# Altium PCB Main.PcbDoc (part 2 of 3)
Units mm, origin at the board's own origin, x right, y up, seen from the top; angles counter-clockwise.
Board outline 160.02 x 109 mm, 4 copper layers (Top Layer, MidLayer1, MidLayer2, Bottom Layer), stack 1.588 mm thick; 313 components, 266 nets, 1154 pads, 499 vias.

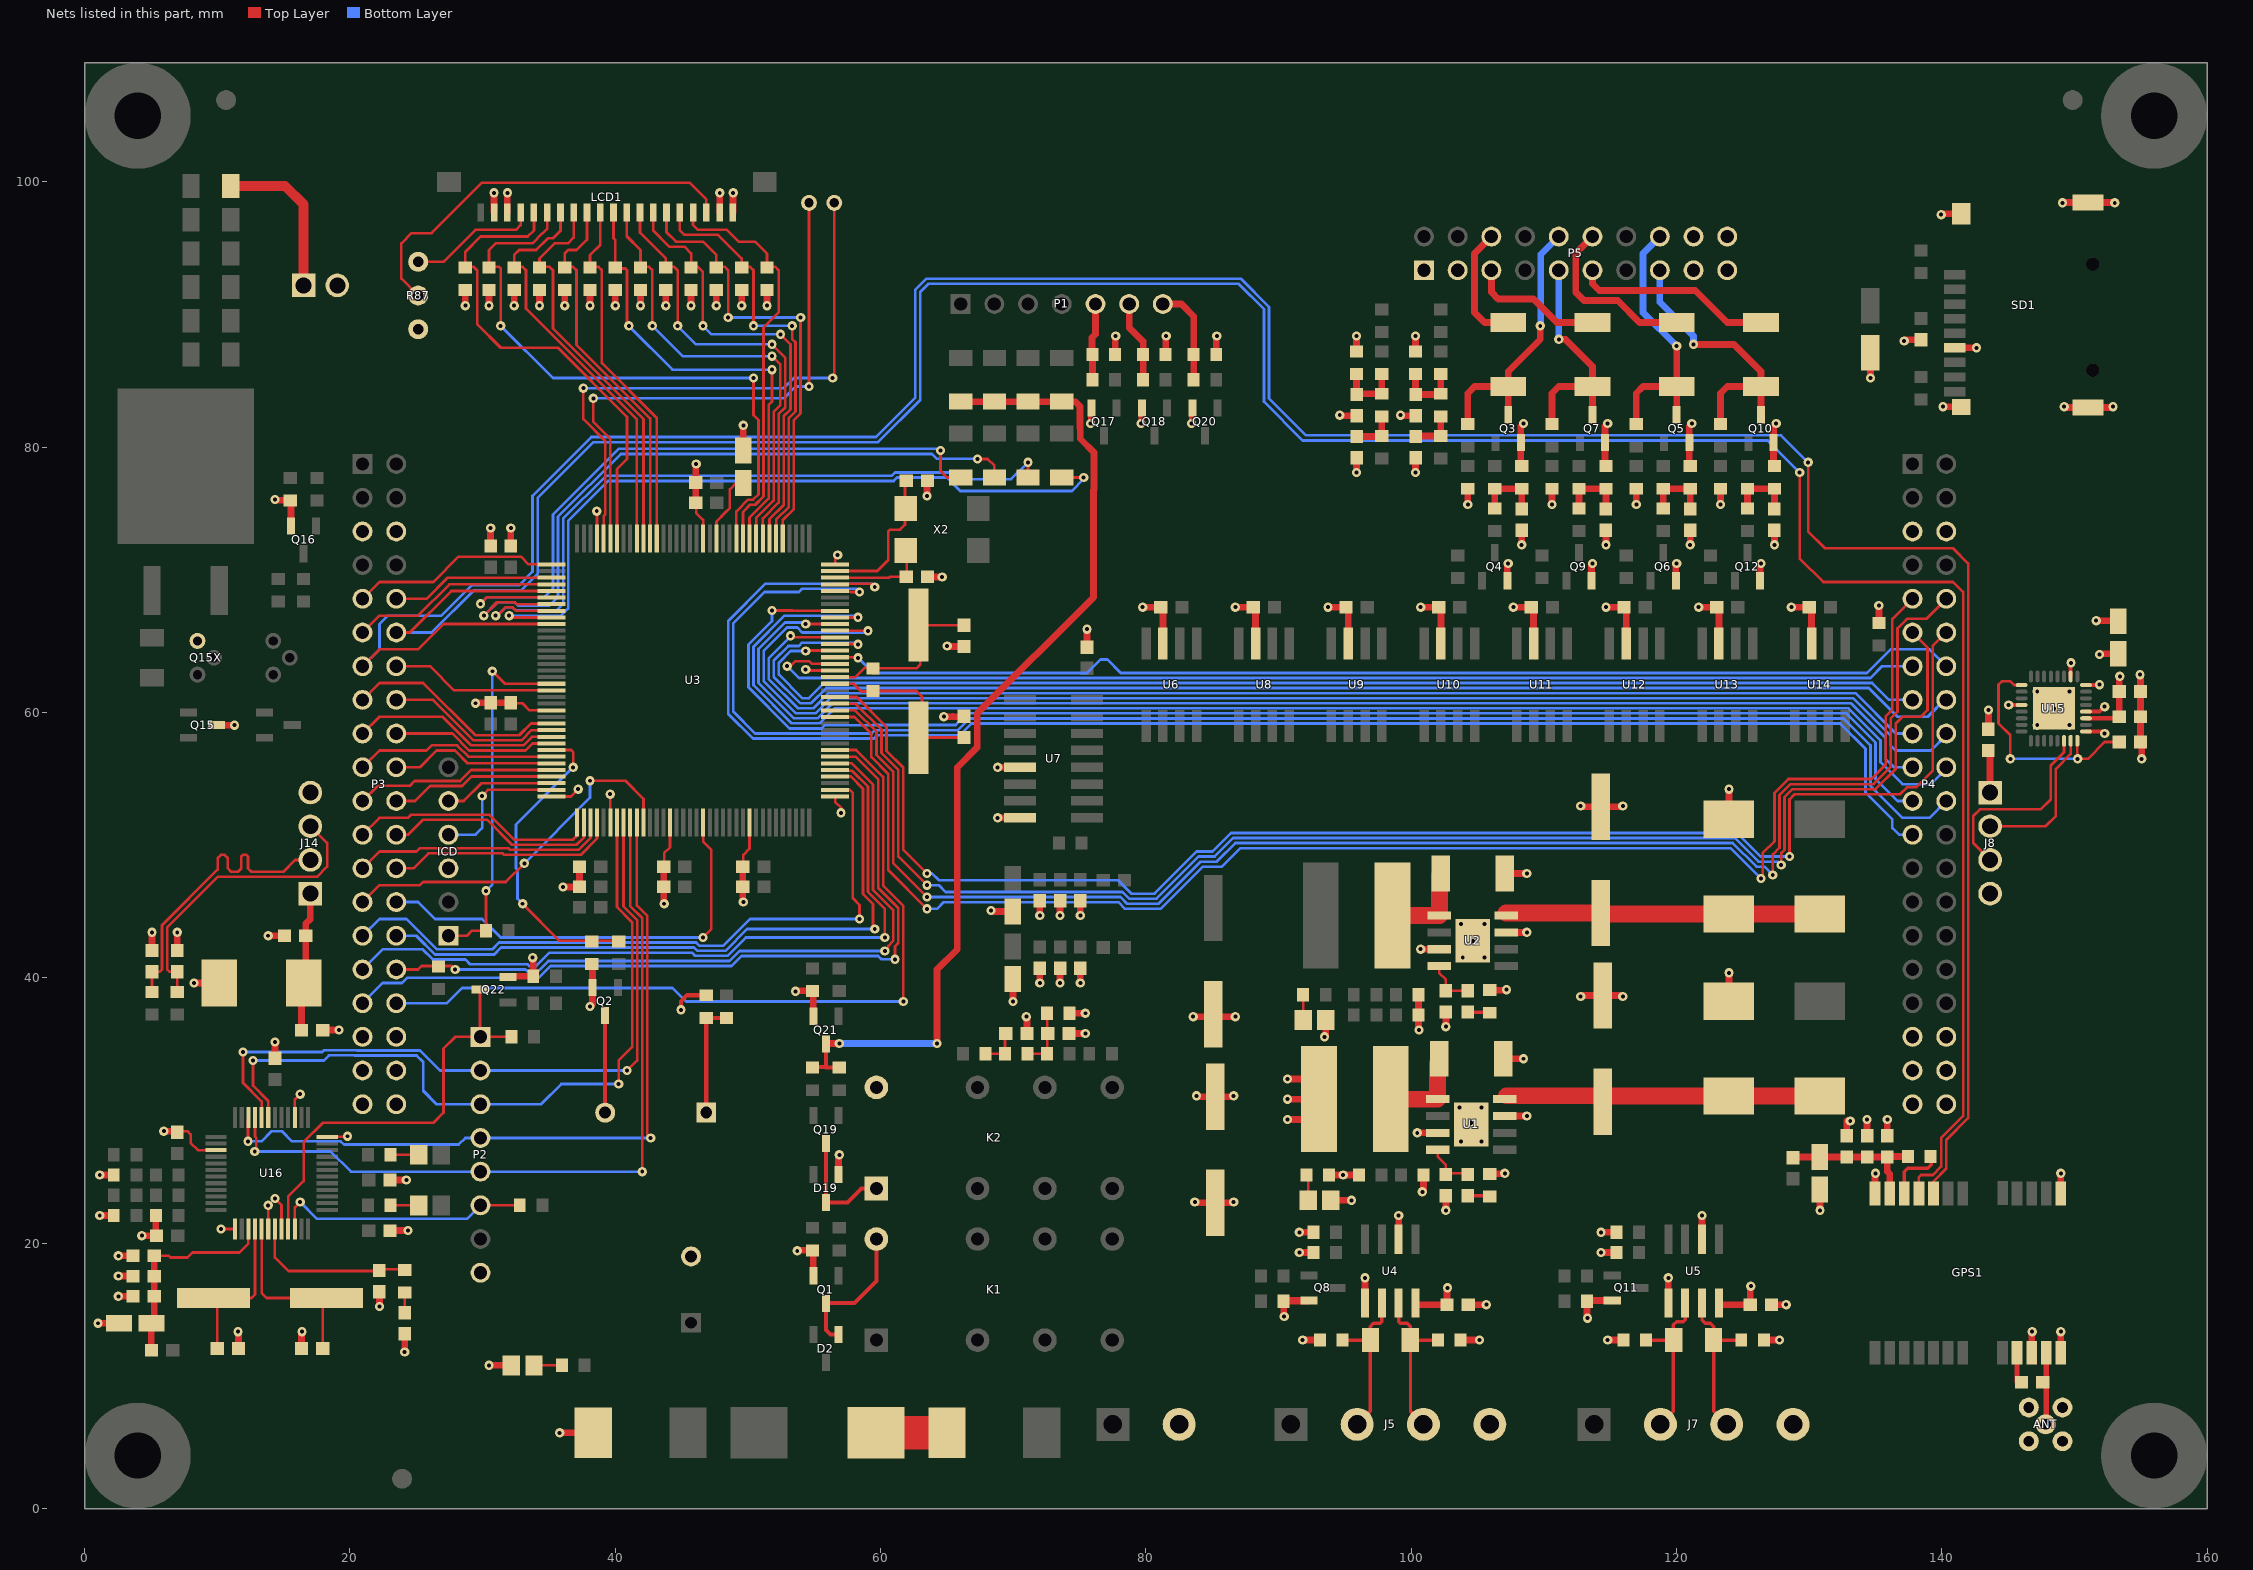
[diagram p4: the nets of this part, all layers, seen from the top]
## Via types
v1: diameter 0.7, hole 0.3, Top Layer to Bottom Layer, tented both sides, 499 vias

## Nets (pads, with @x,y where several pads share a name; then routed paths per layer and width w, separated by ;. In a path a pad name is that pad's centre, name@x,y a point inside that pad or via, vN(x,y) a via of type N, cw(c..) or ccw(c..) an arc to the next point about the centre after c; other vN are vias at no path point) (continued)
+5V: C4.1 C44.1 C46.1 C64.1 C65.1 C66.1 L1.2 L7.2 LCD1.2 P3.5 P3.6 P4.5 P4.6 P5.18 P5.20 R2.1 R3.1 R15.1 R47.1 R48.1 R49.1 R60.1 R61.1 R62.1 R75.1 R76.1 R77.1 R78.1 R79.1 R80.1 R81.1 R82.1 R83.1 R84.1 R85.1 R86.1 R87.1 U4.8 U5.8 U15.19 | length 55.1
  Top Layer w0.305: v1(44.958,37.592) 44.958,38.227 45.427,38.696 R15.1@46.863,38.696 ; U15.19@150.863,59.575 C65.1@153.174,59.575
  Top Layer w0.5: LCD1.2@47.87,97.695 47.87,99.178 v1(47.879,99.187) ; v1(151.892,64.389) 151.937,64.434 C64.1@153.289,64.434 ; C65.1@153.378,59.69 C66.1@153.378,61.595 153.378,62.7 v1(153.416,62.738)
  Top Layer w0.508: L7.2@17.945,36.068 v1(19.177,36.068) ; v1(30.48,90.678) R86.1@30.48,91.86 ; v1(32.385,90.678) R85.1@32.385,91.86 ; v1(34.29,90.678) R84.1@34.29,91.86 ; v1(36.195,90.678) R83.1@36.195,91.86 ; v1(38.1,90.678) R82.1@38.1,91.86 ; v1(40.005,90.678) R81.1@40.005,91.86 ; v1(41.91,90.678) R80.1@41.91,91.86 ; v1(43.815,90.678) R79.1@43.815,91.86 ; v1(45.72,90.678) R78.1@45.72,91.86 ; v1(47.625,90.678) R77.1@47.625,91.86 ; v1(49.53,90.678) R76.1@49.53,91.86 ; v1(51.435,90.678) R75.1@51.435,91.86 ; v1(83.82,31.115) 83.884,31.051 C4.1@85.217,31.051 86.55,31.051 v1(86.614,31.115) ; v1(90.678,29.337) 92.202,29.337 93.058,30.193 L1.2@93.058,30.861 ; v1(90.678,30.861) L1.2@93.058,30.861 ; v1(90.678,32.385) 92.583,32.385 93.058,31.91 L1.2@93.058,30.861 ; v1(91.567,19.304) R48.1@92.622,19.304 ; v1(91.567,20.828) R47.1@92.622,20.828 ; v1(91.821,12.7) R49.1@93.13,12.7 ; R2.1@93.814,25.146 v1(94.869,25.146) R3.1@96.051,25.146 ; U4.8@100.457,15.367 C44.1@102.705,15.367 102.705,16.599 v1(102.743,16.637) ; v1(114.3,19.304) R61.1@115.482,19.304 ; v1(114.3,20.828) R60.1@115.482,20.828 ; v1(114.808,12.7) R62.1@115.99,12.7 ; U5.8@123.317,15.367 C46.1@125.565,15.367 125.565,16.726 v1(125.603,16.764)
+5VUSB: C81.1 C82.1 J14.1 L7.1 | length 10.3
  Top Layer w0.508: L7.1@16.345,36.068 C81.1@16.345,39.154 ; C81.1@16.675,39.154 C82.1@16.675,43.18 16.675,44.107 17.018,44.45 J14.1@17.018,46.228
BUZZER: R17.1 R18.1 U3.29 | length 23.5
  Top Layer w0.203: v1(33.02,45.593) 35.814,42.799 R17.1@40.259,42.799 ; U3.29@35.179,57.177 36.676,57.177 36.83,57.023 v1(36.83,55.88)
  Bottom Layer w0.203: v1(33.02,45.593) 32.639,45.974 32.639,48.137 32.518,48.259 32.518,51.568 v1(36.83,55.88)
C1: P1.5 R95.1 R100.1 | length 5.8
  Top Layer w0.508: R95.1@75.985,85.09 75.985,86.956 75.946,86.995 75.946,88.265 76.2,88.519 P1.5@76.2,90.805
C2: P1.6 R97.1 R101.1 | length 6.2
  Top Layer w0.508: P1.6@78.74,90.805 78.74,89.027 79.795,87.972 R101.1@79.795,86.995 R97.1@79.795,85.09
C3: P1.7 R99.1 R102.1 | length 7.5
  Top Layer w0.508: P1.7@81.28,90.805 82.677,90.805 83.605,89.877 R102.1@83.605,86.995 ; R99.1@83.605,85.09 R102.1@83.605,86.956
DIGI_ANODE1: D11.2 P5.10 Q3.3 R32.1 | length 20.7
  Top Layer w0.508: R32.1@104.267,81.661 R32.1@104.267,81.749 104.267,84.074 104.775,84.582 D11.2@107.315,84.582 ; Q3.3@107.315,82.423 Q3.3@107.315,82.457 D11.2@107.315,84.582 ; v1(109.728,89.154) 109.728,88.138 107.315,85.725 D11.2@107.315,84.582
  Bottom Layer w0.508: v1(109.728,89.154) 109.766,89.192 109.766,94.526 P5.10@111.125,95.885
DIGI_ANODE2: D12.2 P5.16 Q5.3 R44.1 | length 20.7
  Top Layer w0.508: R44.1@116.967,81.661 R44.1@116.967,81.749 116.967,84.074 117.475,84.582 D12.2@120.015,84.582 ; Q5.3@120.015,82.423 Q5.3@120.015,82.457 D12.2@120.015,84.582 ; v1(120.015,87.63) D12.2@120.015,84.582
  Bottom Layer w0.508: P5.16@118.745,95.885 117.475,94.615 117.475,90.17 v1(120.015,87.63)
DIGI_ANODE3: D13.2 P5.9 Q7.3 R57.1 | length 18.1
  Top Layer w0.508: R57.1@110.617,81.661 R57.1@110.617,81.749 110.617,84.074 111.125,84.582 D13.2@113.665,84.582 ; v1(111.125,88.138) 111.633,88.138 113.665,86.106 D13.2@113.665,84.582 ; Q7.3@113.665,82.423 Q7.3@113.665,82.457 D13.2@113.665,84.582
  Bottom Layer w0.508: v1(111.125,88.138) P5.9@111.125,93.345 P5.9@111.125,93.472
DIGI_ANODE4: D14.2 P5.15 Q10.3 R69.1 | length 21.5
  Top Layer w0.508: v1(121.285,87.757) 124.333,87.757 126.365,85.725 D14.2@126.365,84.582 ; R69.1@123.317,81.661 R69.1@123.317,81.749 123.317,84.074 123.825,84.582 D14.2@126.365,84.582 ; Q10.3@126.365,82.423 Q10.3@126.365,82.457 D14.2@126.365,84.582
  Bottom Layer w0.508: P5.15@118.745,93.345 118.745,90.932 121.285,88.392 v1(121.285,87.757)
DIGI_CATHODE1: D11.1 P5.6 | length 9.1
  Top Layer w0.508: P5.6@106.045,95.885 104.775,94.615 104.775,90.17 105.537,89.408 D11.1@107.315,89.408
DIGI_CATHODE2: D12.1 P5.12 | length 13.3
  Top Layer w0.508: P5.12@113.665,95.885 112.395,94.615 112.395,91.694 113.03,91.059 115.57,91.059 117.221,89.408 D12.1@120.015,89.408
DIGI_CATHODE3: D13.1 P5.5 | length 10.2
  Top Layer w0.508: P5.5@106.045,93.345 106.045,91.694 106.553,91.186 109.22,91.186 110.998,89.408 D13.1@113.665,89.408
DIGI_CATHODE4: D14.1 P5.11 | length 14.9
  Top Layer w0.508: P5.11@113.665,93.345 113.665,92.329 114.173,91.821 121.412,91.821 123.825,89.408 D14.1@126.365,89.408
GND: ANT.2 ANT.3 ANT.4 ANT.5 C1.2 C2.2 C3.2 C4.2 C6.2 C7.2 C9.2 C10.2 C11.2 C12.2 C13.2 C14.2 C15.2 C16.2 C17.2 C18.2 C19.2 C20.2 C21.2 C22.2 C23.2 C24.2 C25.2 C26.2 C27.2 C28.2 C29.2 C30.2 C31.2 C32.2 C33.2 C34.2 C35.2 C36.2 C37.2 C38.2 C39.2 C40.2 C41.2 C42.2 C43.2 C44.2 C45.2 C46.2 C47.2 C48.2 C49.2 C51.2 C53.2 C54.2 C57.2 C58.2 C61.2 C62.2 C64.2 C65.2 C66.2 C67.2 C68.2 C69.2 C70.2 C71.2 C72.2 C73.2 C74.2 C75.2 C76.2 C77.2 C78.2 C79.2 C80.2 C81.2 C82.2 C83.2 C84.2 C85.2 C86.2 C87.2 C88.2 C89.2 C90.2 D4.2 D6.2 D7.2 D9.2 D10.2 D19.1 GPS1.10 GPS1.12 GPS1.13 GPS1.24 ICD.3 J5.4 J7.4 J8.4 J11.2 J14.4 K2.16 LCD1.1 LCD1.18 LCD1.19 LED1.1 LED2.1 LED3.1 P2.8 P3.35 P3.36 P3.37 P3.38 P3.39 P3.40 P4.35 P4.36 P4.37 P4.38 P4.39 P4.40 P5.1 P5.3 P5.17 P5.19 Q1.2 Q2.2 Q3.2 Q4.2 Q5.2 Q6.2 Q7.2 Q8.2 Q9.2 Q10.2 Q11.2 Q12.2 Q15.3 Q15X.1 Q16.2 Q17.2 Q18.2 Q20.2 Q21.2 Q22.2 R4.2 R5.2 R7.2 R11.2 R12.2 R13.2 R18.2 R24.2 R27.2 R34.2 R35.2 R40.2 R43.2 R46.2 R54.2 R55.2 R56.2 R59.2 R66.2 R68.2 R71.2 R72.2 R73.2 R88.2 R94.2 R100.2 R101.2 R102.2 R104.2 R107.2 R115.2 R116.2 R117.2 SD1.6 SD1.10 SD1.11 SD1.12 SD1.13 U1.3 U1.7 U1.9 U2.3 U2.7 U2.9 U3.23 U3.36 U3.42 U3.51 U3.63 U3.73 U3.92 U3.108 U3.125 U3.141 U4.2 U4.5 U5.2 U5.5 U6.7 U7.5 U7.8 U8.7 U9.7 U10.7 U11.7 U12.7 U13.7 U14.7 U15.4 U15.17 U15.20 U15.24 U15.26 U15.33 U16.1 U16.6 U16.8 U16.24 U16.27 U16.39 VIN.2 | length 328.1
  Top Layer w0.203: C76.2@6.858,28.448 6.896,28.448 7.747,28.448 8.001,28.194 8.001,27.559 8.538,27.022 U16.39@9.896,27.022 ; v1(10.287,21.082) 10.296,21.073 U16.1@11.347,21.073 ; v1(13.843,22.86) 13.846,22.857 U16.6@13.846,21.073 ; v1(14.351,23.368) 14.846,22.873 U16.8@14.846,21.073 ; U16.27@15.846,29.473 15.846,30.832 v1(16.256,31.242) ; U16.24@18.296,28.022 19.767,28.022 v1(19.812,28.067) ; C20.2@32.131,60.706 33.02,60.706 33.55,60.176 U3.23@35.179,60.176 ; U3.36@35.179,53.678 36.66,53.678 v1(37.211,54.229) ; v1(35.814,5.715) v1@35.941,5.715 ; v1(38.608,75.184) 38.631,75.161 U3.141@38.631,73.126 ; v1(39.624,53.848) 39.631,53.841 U3.42@39.631,51.726 ; C24.2@43.688,48.387 43.688,49.403 44.129,49.844 U3.51@44.129,51.726 ; C28.2@46.101,75.819 46.101,75.057 46.629,74.529 U3.125@46.629,73.126 ; C26.2@49.657,48.26 49.657,49.276 50.128,49.747 U3.63@50.128,51.726 ; v1(54.356,63.246) 54.426,63.176 U3.92@56.579,63.176 ; U3.73@56.579,53.678 56.579,53.276 57.023,52.832 v1(57.023,52.451) ; U3.108@56.579,71.174 56.579,71.692 v1(56.769,71.882)
  Top Layer w0.305: v1(145.034,60.579) 145.038,60.575 U15.4@146.013,60.575 ; U15.26@149.713,62.725 149.713,63.734 v1(149.733,63.754) ; U15.17@150.863,58.575 152.118,58.575 v1(152.273,58.42) ; U15.20@150.863,60.075 151.896,60.075 v1(152.273,60.452) ; U15.24@150.863,62.075 151.864,62.075 v1(151.892,62.103)
  Top Layer w0.508: v1(1.016,13.97) C69.2@2.585,13.97 ; v1(1.143,22.098) R117.2@2.198,22.098 ; v1(1.143,25.146) R116.2@2.198,25.146 ; v1(2.54,16.002) C72.2@3.645,16.002 ; v1(2.54,17.526) C71.2@3.645,17.526 ; v1(2.54,19.05) C70.2@3.645,19.05 ; v1(4.318,20.574) 5.334,20.574 5.373,20.613 R115.2@5.373,22.098 ; C78.2@5.08,42.075 v1(5.08,43.434) ; v1(5.969,28.448) C76.2@6.858,28.448 ; C76.2@6.896,28.448 C76.2@6.985,28.359 ; C79.2@6.985,42.075 v1(6.985,43.434) ; v1(8.255,39.624) C81.2@10.16,39.624 ; Q15.3@9.94,59.055 v1(11.303,59.055) ; v1(11.557,13.335) 11.595,13.297 C84.2@11.595,12.065 ; v1(13.843,43.18) C82.2@15.075,43.18 ; C75.2@14.351,33.947 v1(14.351,35.179) ; v1(14.351,76.073) 14.412,76.012 15.56,76.012 Q16.2@15.56,74.075 ; C85.2@16.345,12.065 16.345,13.297 v1(16.383,13.335) ; v1(22.225,15.24) C80.2@22.225,16.345 ; C77.2@23.025,20.955 v1(24.384,20.955) ; C74.2@23.025,24.765 v1(24.257,24.765) ; v1(24.13,11.811) C83.2@24.13,13.17 ; v1(28.702,90.678) R88.2@28.702,91.86 ; v1(29.464,60.706) 29.502,60.744 C21.2@30.607,60.744 ; v1(30.48,10.795) LED1.1@32.17,10.795 ; C19.2@30.607,72.555 v1(30.607,73.914) ; C21.2@30.696,60.744 C20.2@32.131,60.744 ; v1(30.861,99.187) 30.87,99.178 LCD1.19@30.87,97.695 ; LCD1.18@31.87,97.695 31.87,99.18 v1(31.877,99.187) ; Q22.2@31.877,40.132 R107.2@33.821,40.132 33.821,41.49 v1(33.782,41.529) ; C18.2@32.131,72.555 v1(32.131,73.914) ; v1@35.941,5.715 D4.2@38.34,5.715 ; v1(36.068,46.863) C22.2@37.3,46.863 ; C22.2@37.3,46.901 C23.2@37.3,48.387 ; v1(38.1,37.846) 38.293,38.039 Q2.2@38.293,39.277 R18.2@38.293,40.96 ; C25.2@43.65,46.863 43.65,45.631 v1(43.688,45.593) ; C25.2@43.65,46.901 C24.2@43.65,48.387 ; C28.2@46.063,75.819 C29.2@46.063,77.305 ; C29.2@46.063,77.343 46.063,78.702 v1(46.101,78.74) ; LCD1.1@48.87,97.695 48.87,99.162 v1(48.895,99.187) ; C27.2@49.619,46.863 49.619,45.758 v1(49.657,45.72) ; C27.2@49.619,46.901 C26.2@49.619,48.387 ; C30.2@49.657,79.756 v1(49.657,81.661) ; v1(53.594,38.989) 53.633,39.028 R104.2@54.864,39.028 ; v1(53.721,19.431) 53.76,19.47 R7.2@54.864,19.47 ; Q1.2@54.93,17.56 R7.2@54.93,19.492 ; Q21.2@54.93,37.118 R104.2@54.93,39.055 ; D19.1@56.83,25.18 56.83,26.604 v1(56.896,26.67) ; v1(63.5,76.327) 63.5,77.432 C34.2@63.538,77.47 ; C33.2@63.538,70.231 v1(64.643,70.231) ; v1(64.77,59.69) 65.405,59.69 ; v1(65.024,65.024) 65.062,64.986 C32.2@66.294,64.986 ; 65.443,59.728 65.405,59.69 ; C31.2@66.294,59.69 65.405,59.69 ; v1(68.326,45.085) 68.408,45.003 C10.2@69.977,45.003 ; v1(68.834,52.07) 68.839,52.075 U7.8@70.5,52.075 ; v1(68.834,55.88) 68.839,55.885 U7.5@70.5,55.885 ; v1(69.977,38.227) C14.2@69.977,39.923 ; v1(70.993,37.084) 71.031,37.046 C36.2@71.031,35.814 ; v1(72.009,39.624) C17.2@72.009,40.729 ; v1(72.009,44.704) C13.2@72.009,45.809 ; v1(73.533,39.624) C16.2@73.533,40.729 ; v1(73.533,44.704) C12.2@73.533,45.809 ; C35.2@74.206,35.814 v1(75.438,35.814) ; R24.2@74.256,37.338 v1(75.438,37.338) ; v1(75.057,39.624) C15.2@75.057,40.729 ; v1(75.057,44.704) C11.2@75.057,45.809 ; C51.2@75.565,64.935 v1(75.565,66.294) ; v1(75.819,81.788) 75.885,81.854 Q17.2@75.885,82.965 ; R100.2@77.685,86.995 77.685,88.353 v1(77.724,88.392) ; v1(79.629,81.788) 79.695,81.854 Q18.2@79.695,82.965 ; v1(79.756,67.945) C48.2@81.115,67.945 ; U6.7@81.285,65.201 C48.2@81.285,67.813 ; R101.2@81.495,86.995 81.495,88.353 v1(81.534,88.392) ; v1(83.439,81.788) 83.505,81.854 Q20.2@83.505,82.965 ; v1(83.566,37.084) 84.899,37.084 C7.2@85.09,37.275 85.407,37.275 85.598,37.084 v1(86.741,37.084) ; v1(83.693,23.114) 83.756,23.051 C4.2@85.217,23.051 86.551,23.051 v1(86.614,23.114) ; R102.2@85.305,86.995 85.305,88.353 v1(85.344,88.392) ; v1(86.741,67.945) C49.2@88.1,67.945 ; U8.7@88.27,65.201 C49.2@88.27,67.813 ; v1(90.424,14.478) 90.385,14.517 R56.2@90.385,15.621 Q8.2@92.202,15.621 ; R56.2@90.49,15.687 Q8.2@92.295,15.687 ; v1(93.472,35.56) 93.56,35.648 LED3.1@93.56,36.83 ; v1(93.726,67.945) C53.2@95.085,67.945 ; LED2.1@93.941,23.241 v1(95.504,23.241) ; v1(94.615,82.423) 94.653,82.385 C38.2@95.885,82.385 ; U9.7@95.255,65.201 C53.2@95.255,67.813 ; v1(95.885,78.105) C39.2@95.885,79.21 ; R34.2@95.885,87.21 v1(95.885,88.392) ; U4.5@96.52,15.507 v1(96.52,17.399) ; U4.2@99.06,20.307 v1(99.06,22.098) ; v1(99.187,82.423) 99.225,82.385 C40.2@100.33,82.385 ; v1(100.33,78.105) C41.2@100.33,79.21 ; R40.2@100.33,87.21 v1(100.33,88.392) ; v1(100.457,28.321) U1.3@101.994,28.321 ; R12.2@100.545,38.647 R13.2@100.545,37.211 100.545,36.107 v1(100.584,36.068) ; v1(100.711,42.164) U2.3@102.121,42.164 ; v1(100.711,67.945) C54.2@102.07,67.945 ; v1(100.838,23.876) 100.926,23.964 R5.2@100.926,25.146 ; U10.7@102.24,65.201 C54.2@102.24,67.813 ; v1(102.616,22.479) C6.2@102.616,23.584 ; v1(102.616,36.322) C9.2@102.616,37.427 ; v1(103.632,30.226) U1.9@104.521,29.337 ; R54.2@103.72,12.7 v1(105.156,12.7) ; v1(103.759,27.686) U1.9@104.521,28.448 ; v1(103.759,44.069) 103.759,43.688 v1(104.648,42.799) ; v1(103.886,41.529) 104.648,42.291 U2.9@104.648,42.418 ; v1(104.267,75.692) R35.2@104.267,76.874 ; C44.2@104.305,15.367 v1(105.664,15.367) ; v1(105.283,27.686) U1.9@104.521,28.448 ; v1(105.283,30.226) 104.521,29.464 U1.9@104.521,29.337 ; v1(105.537,41.529) U2.9@104.648,42.418 ; v1(105.537,44.069) 105.537,43.688 v1(104.648,42.799) ; R4.2@105.918,25.234 107.022,25.234 v1(107.061,25.273) ; R11.2@105.918,39.077 107.149,39.077 v1(107.188,39.116) ; D6.2@106.934,33.909 v1(108.458,33.909) ; U1.7@107.048,29.591 v1(108.712,29.591) ; D10.2@107.061,47.879 v1(108.712,47.879) ; U2.7@107.175,43.434 v1(108.712,43.434) ; Q4.2@107.249,69.943 107.249,71.181 v1(107.315,71.247) ; v1(107.696,67.945) C57.2@109.055,67.945 ; R27.2@108.265,78.552 Q3.2@108.265,80.357 108.265,81.595 v1(108.458,81.788) ; v1(108.331,72.644) C37.2@108.331,73.749 ; U11.7@109.225,65.201 C57.2@109.225,67.813 ; v1(110.617,75.692) R59.2@110.617,76.874 ; v1(112.776,38.608) 112.839,38.671 C3.2@114.427,38.671 115.888,38.671 v1(115.951,38.608) ; v1(112.776,52.959) 112.84,52.895 C2.2@114.3,52.895 115.887,52.895 v1(115.951,52.959) ; R71.2@113.245,15.621 113.245,14.39 v1(113.284,14.351) ; R71.2@113.345,15.687 Q11.2@115.155,15.687 ; Q9.2@113.599,69.943 113.599,71.181 v1(113.665,71.247) ; R55.2@114.615,78.552 Q7.2@114.615,80.357 114.615,81.595 v1(114.808,81.788) ; v1(114.681,67.945) C58.2@116.04,67.945 ; v1(114.681,72.644) C43.2@114.681,73.749 ; U12.7@116.21,65.201 C58.2@116.21,67.813 ; v1(116.967,75.692) R46.2@116.967,76.874 ; U5.5@119.38,15.507 v1(119.38,17.399) ; Q6.2@119.949,69.943 119.949,71.181 v1(120.015,71.247) ; R43.2@120.965,78.552 Q5.2@120.965,80.357 120.965,81.595 v1(121.158,81.788) ; v1(121.031,72.644) C42.2@121.031,73.749 ; v1(121.666,67.945) C61.2@123.025,67.945 ; U5.2@121.92,20.307 v1(121.92,22.098) ; U13.7@123.195,65.201 C61.2@123.195,67.813 ; v1(123.317,75.692) R72.2@123.317,76.874 ; D7.2@123.952,38.241 v1(123.952,40.386) ; D9.2@123.952,51.957 v1(123.952,54.229) ; Q12.2@126.299,69.943 126.299,71.181 v1(126.365,71.247) ; R68.2@126.58,12.7 v1(127.762,12.7) ; C46.2@127.165,15.367 v1(128.27,15.367) ; R66.2@127.315,78.552 Q10.2@127.315,80.357 127.315,81.595 v1(127.508,81.788) ; v1(127.381,72.644) C45.2@127.381,73.749 ; v1(128.651,67.945) C62.2@130.01,67.945 ; U14.7@130.18,65.201 C62.2@130.18,67.813 ; v1(130.81,22.479) C86.2@130.81,24.048 ; C89.2@132.842,28.105 132.842,29.21 v1(133.096,29.21) ; C88.2@134.366,28.105 v1(134.366,29.337) ; v1(134.62,85.217) C47.2@134.62,87.122 ; GPS1.24@134.971,23.749 134.971,25.243 v1(135.001,25.273) ; R73.2@135.255,66.763 v1(135.255,68.072) ; C87.2@135.89,28.105 v1(135.89,29.337) ; v1(137.16,88.011) 137.249,88.1 C90.2@138.43,88.1 ; v1(139.954,97.536) 140.017,97.599 SD1.11@141.47,97.599 ; v1(140.081,83.058) 140.09,83.049 SD1.10@141.47,83.049 ; SD1.6@140.97,87.499 142.617,87.499 v1(142.621,87.503) ; C67.2@143.51,58.75 v1(143.51,60.198) ; GPS1.10@146.771,11.749 146.771,13.294 v1(146.812,13.335) ; v1(147.193,59.055) v1(148.463,60.325) ; v1(147.193,61.595) v1(148.463,60.325) ; GPS1.12@148.971,11.749 v1(148.971,13.335) ; GPS1.13@148.971,23.749 v1(148.971,25.273) ; v1(149.098,98.425) 149.122,98.449 SD1.12@151.02,98.449 153.011,98.449 v1(153.035,98.425) ; v1(149.225,83.058) 149.284,82.999 SD1.13@151.02,82.999 152.849,82.999 v1(152.908,83.058) ; v1(149.606,59.055) 149.606,59.182 v1(148.463,60.325) ; v1(149.606,61.595) 148.463,60.452 v1(148.463,60.325) ; v1(151.638,66.929) 153.244,66.929 C64.2@153.289,66.884 ; v1(154.94,62.865) 154.978,62.827 C66.2@154.978,61.595 ; C68.2@154.978,57.785 155.067,57.696 v1(155.067,56.515) ; C68.2@154.978,57.823 C65.2@154.978,59.69 C66.2@154.978,61.43 ; U1.9@104.521,28.448 U1.9@104.521,28.956 v1(104.521,29.083) U1.9@104.521,29.337 ; U2.9@104.648,42.418 v1(104.648,42.799)
ICD_NMCLR: ICD.1 R14.2 U3.19 | length 27.5
  Top Layer w0.203: ICD.1@27.432,43.18 28.829,43.18 29.21,43.561 R14.2@30.226,43.561 ; R14.2@30.265,43.561 v1(30.265,46.57) ; v1(30.734,63.119) 31.677,62.176 U3.19@35.179,62.176
  Bottom Layer w0.203: v1(30.265,46.57) 30.734,47.039 v1(30.734,63.119)
IDC_PGC: ICD.5 U3.34 | length 8.3
  Top Layer w0.203: ICD.5@27.432,53.34 28.575,53.34 29.913,54.678 U3.34@35.179,54.678
IDC_PGD: ICD.4 U3.35 | length 10.6
  Top Layer w0.203: v1(29.972,53.721) 29.96,53.733 30.404,54.178 U3.35@35.179,54.178
  Bottom Layer w0.203: ICD.4@27.432,50.8 29.464,50.8 29.972,51.308 v1(29.972,53.721)
NetANT_1: ANT.1 GPS1.11 L8.1 | length 5.3
  Top Layer w0.381: ANT.1@147.871,6.434 GPS1.11@147.871,11.749
NetBUZ1_1: BUZ1.1 R15.2 R16.2 | length 8.3
  Top Layer w0.305: BUZ1.1@46.863,29.845 R15.2@46.863,36.996 47.967,36.996 R16.2@48.006,36.957
NetBUZ1_2: BUZ1.2 Q2.3 | length 7.3
  Top Layer w0.305: BUZ1.2@39.243,29.845 Q2.3@39.243,37.177
NetC2_1: C2.1 D8.1 D9.1 U2.8 | length 23.4
  Top Layer w1.27: U2.8@107.125,44.895 C2.1@114.3,44.895 ; C2.1@114.54,44.817 D9.1@123.952,44.817 D8.1@130.81,44.817
NetC3_1: C3.1 D5.1 D7.1 U1.8 | length 23.8
  Top Layer w1.27: U1.8@107.188,31.115 113.983,31.115 C3.1@114.427,30.671 ; C3.1@114.441,31.101 D7.1@123.952,31.101 D5.1@130.81,31.101
NetC5_1: C5.1 C6.1 U1.4 | length 3.9
  Top Layer w0.2: U1.4@101.994,27.051 101.994,26.53 102.616,25.908 C6.1@102.616,25.184 102.616,25.146 102.743,25.273 C5.1@104.267,25.273
NetC5_2: C5.2 R4.1 | length 1.7
  Top Layer w0.254: C5.2@104.267,23.584 R4.1@106.007,23.584
NetC8_1: C8.1 C9.1 U2.4 | length 3.7
  Top Layer w0.2: U2.4@102.108,40.894 102.108,40.386 102.616,39.878 102.616,39.116 102.705,39.027 C8.1@104.267,39.027
NetC8_2: C8.2 R11.1 | length 1.6
  Top Layer w0.254: C8.2@104.267,37.427 R11.1@105.829,37.427
NetC30_1: C30.1 U3.123 | length 5.2
  Top Layer w0.203: U3.123@47.629,73.126 47.629,74.395 48.006,74.772 48.006,74.803 48.268,75.065 48.279,75.065 48.641,75.427 48.641,76.835 49.149,77.343 C30.1@49.53,77.343
NetC31_1: C31.1 R19.1 U3.90 X1.1 | length 13
  Top Layer w0.203: U3.90@56.579,62.176 57.966,62.176 58.547,61.595 R19.1@59.563,61.595 ; R19.1@59.436,61.634 62.699,61.634 63.119,61.214 X1.1@63.119,58.674 ; X1.1@63.284,58.128 C31.1@66.294,58.128 C31.1@66.675,58.128
NetC32_1: C32.1 R19.2 U3.91 X1.2 | length 13.4
  Top Layer w0.203: U3.91@56.579,62.676 58.104,62.676 58.801,63.373 R19.2@59.436,63.373 ; R19.2@59.436,63.334 62.699,63.334 62.992,63.627 62.992,66.548 63.03,66.586 C32.1@66.294,66.586 C32.1@66.675,66.586
NetC33_1: C33.1 U3.106 X2.1 | length 7.5
  Top Layer w0.203: U3.106@56.579,70.174 60.649,70.174 60.706,70.231 C33.1@61.938,70.231 61.976,70.231 61.976,72.136 X2.1@62.103,72.263
NetC34_1: C34.1 U3.107 X2.4 | length 11.5
  Top Layer w0.203: U3.107@56.579,70.674 59.752,70.674 60.579,71.501 60.579,73.66 60.706,73.787 61.468,73.787 61.849,74.168 61.849,77.47 C34.1@61.976,77.597
NetC35_1: C35.1 R21.2 R22.1 R24.1 | length 4.2
  Top Layer w0.203: R22.1@71.12,34.29 R21.2@72.556,34.29 72.556,35.648 C35.1@72.517,35.687 ; C35.1@72.556,36.029 R24.1@72.556,37.338
NetC36_1: C36.1 R22.2 R23.1 | length 3
  Top Layer w0.203: R23.1@67.818,34.29 R23.1@67.906,34.29 R22.2@69.381,34.29 C36.1@69.381,35.726
NetC37_1: C37.1 R25.2 R26.1 R27.1 | length 4.7
  Top Layer w0.508: R26.1@106.299,75.565 R25.2@106.299,76.874 ; R25.2@106.514,76.874 R27.1@108.331,76.874 C37.1@108.331,75.349
NetC38_1: C38.1 R29.2 R30.1 R34.1 | length 4.8
  Top Layer w0.508: C38.1@95.885,83.985 R34.1@95.885,85.471 ; C38.1@96.051,84.035 R30.1@97.79,84.035 R29.2@97.79,85.51 R29.2@97.79,85.598 ; R30.1@97.79,83.985 R30.1@97.828,83.985
NetC39_1: C39.1 R30.2 R31.1 | length 3.3
  Top Layer w0.508: C39.1@95.885,80.81 R31.1@97.701,80.81 ; R31.1@97.701,80.86 R31.1@97.701,81.026 ; R31.1@97.79,81.026 R30.2@97.79,82.335
NetC40_1: C40.1 R37.2 R38.1 R40.1 | length 5
  Top Layer w0.508: R40.1@100.33,85.598 R40.1@100.33,85.51 C40.1@100.33,83.985 R38.1@102.146,83.985 ; R38.1@102.235,84.035 R37.2@102.235,85.51 R37.2@102.235,85.598
NetC41_1: C41.1 R38.2 R39.1 | length 3.3
  Top Layer w0.508: C41.1@100.242,80.86 R39.1@102.235,80.86 ; R39.1@102.235,81.026 R38.2@102.235,82.335
NetC42_1: C42.1 R41.2 R42.1 R43.1 | length 4.7
  Top Layer w0.508: R42.1@118.999,75.565 R41.2@118.999,76.874 ; R41.2@119.214,76.874 R43.1@121.031,76.874 C42.1@121.031,75.349
NetC43_1: C43.1 R51.2 R52.1 R55.1 | length 4.7
  Top Layer w0.508: R52.1@112.649,75.565 R51.2@112.649,76.874 ; R51.2@112.864,76.874 R55.1@114.681,76.874 C43.1@114.681,75.349
NetC45_1: C45.1 R63.2 R64.1 R66.1 | length 4.7
  Top Layer w0.508: R64.1@125.349,75.565 R63.2@125.349,76.874 ; R63.2@125.564,76.874 R66.1@127.381,76.874 C45.1@127.381,75.349
NetC67_1: C67.1 J8.1 | length 3.2
  Top Layer w0.508: C67.1@143.51,57.15 143.637,57.023 J8.1@143.637,53.975
NetC68_1: C68.1 U15.1 U15.16 | length 17.9
  Top Layer w0.203: v1(145.161,56.515) 145.161,58.293 144.272,59.182 144.272,62.103 144.526,62.357 145.161,62.357 145.443,62.075 U15.1@146.013,62.075 ; v1@150.213,56.67 U15.16@150.213,57.875 ; v1(150.241,56.515) 151.003,56.515 152.273,57.785 C68.1@153.378,57.785
  Bottom Layer w0.203: v1(145.161,56.515) v1(150.241,56.515)
NetC69_1: C69.1 C70.1 C71.1 C72.1 L6.2 U16.3 | length 15.4
  Top Layer w0.203: C70.1@5.334,19.05 6.35,19.05 6.477,18.923 7.747,18.923 8.128,19.304 11.684,19.304 12.347,19.967 U16.3@12.347,21.073
  Top Layer w0.508: L6.2@5.035,11.983 C69.1@5.035,13.97 ; C69.1@5.042,13.97 C69.1@5.042,14.059 ; C69.1@5.245,14.135 C72.1@5.245,16.002 C71.1@5.245,17.437 ; C71.1@5.245,17.526 C70.1@5.245,18.961
NetC78_1: C78.1 J14.2 R111.1 | length 23
  Top Layer w0.203: R111.1@5.08,38.95 C78.1@5.08,40.475 5.677,40.475 5.842,40.64 5.842,43.973 10.033,48.164 10.033,49.022 10.287,49.276 10.541,49.276 10.795,49.022 10.795,48.26 11.049,48.006 11.557,48.006 11.811,48.26 11.811,49.149 11.938,49.276 12.192,49.276 12.319,49.149 12.319,48.26 12.573,48.006 14.986,48.006 15.875,48.895 J14.2@17.018,48.895
NetC79_1: C79.1 J14.3 R113.1 | length 23.1
  Top Layer w0.203: R113.1@6.985,38.95 C79.1@6.985,40.475 6.388,40.475 6.223,40.64 6.223,43.815 10.033,47.625 17.526,47.625 18.288,48.387 18.288,50.165 J14.3@17.018,51.435
NetC80_1: C80.1 R118.1 U16.7 | length 12.4
  Top Layer w0.203: U16.7@14.346,21.073 14.346,18.928 15.367,17.907 22.225,17.907 22.352,18.034 R118.1@24.13,18.034
NetC83_1: C83.1 R118.2 | length 1.5
  Top Layer w0.203: C83.1@24.13,14.77 R118.2@24.13,16.256
NetC84_1: C84.1 U16.4 X3.1 | length 11.7
  Top Layer w0.203: X3.1@9.779,15.875 12.573,15.875 12.847,16.149 U16.4@12.847,21.073 ; C84.1@9.995,12.065 X3.1@9.995,15.659
NetC85_1: C85.1 U16.5 X3.2 | length 13.5
  Top Layer w0.203: U16.5@13.346,21.073 13.346,16.245 13.716,15.875 X3.2@18.22,15.875 X3.2@18.288,15.875 ; C85.1@17.945,12.065 X3.2@17.945,15.659
NetC86_1: C86.1 C87.1 C88.1 C89.1 GPS1.23 L9.1 R123.2 | length 11.3
  Top Layer w0.508: L9.1@128.86,26.498 C86.1@130.81,26.498 ; C86.1@130.772,26.505 C89.1@132.842,26.505 ; C89.1@132.931,26.505 C88.1@134.366,26.505 ; C88.1@134.582,26.505 C87.1@135.89,26.505 ; GPS1.23@136.071,23.749 136.071,25.219 135.89,25.4 C87.1@135.89,26.505 ; R123.2@137.541,26.416 137.414,26.543 135.89,26.543 C87.1@135.89,26.505
NetD1_1: D1.1 D3.1 | length 5.1
  Top Layer w2.54: D3.1@59.944,5.715 D1.1@65.01,5.715
NetD2_1: D2.1 K1.16 Q1.3 | length 10.8
  Top Layer w0.305: D2.1@56.83,13.115 56.227,13.115 55.88,13.462 Q1.3@55.88,15.46 55.88,15.494 58.039,15.494 59.69,17.145 K1.16@59.69,20.32
NetD6_1: D6.1 L1.1 U1.1 | length 6.2
  Top Layer w1.27: L1.1@98.425,30.861 L1.1@98.458,30.861 U1.1@101.994,30.861 D6.1@101.994,33.541
NetD10_1: D10.1 L2.1 U2.1 | length 6.5
  Top Layer w1.27: L2.1@98.679,44.704 U2.1@102.121,44.704 D10.1@102.121,47.739
NetD15_2: D15.2 D17.2 D20.2 D22.2 Q21.3 R96.2 R98.2 | length 74.8
  Top Layer w0.305: R96.2@54.737,33.274 55.88,33.274 Q21.3@55.88,35.018 ; 55.88,33.235 R98.2@56.896,33.235
  Top Layer w0.508: Q21.3@55.88,35.052 v1(56.896,35.052) ; v1(64.262,35.052) 64.262,40.64 65.786,42.164 65.786,55.88 67.285,57.379 67.285,59.922 76.053,68.691 76.053,76.778 76.093,76.817 76.093,79.609 75.057,80.645 75.057,81.425 75.037,81.444 75.037,83.078 74.675,83.44 D22.2@73.66,83.44 71.121,83.44 D20.2@71.12,83.44 D15.2@66.04,83.44
  Bottom Layer w0.508: v1(56.896,35.052) v1(64.262,35.052)
NetD16_2: D16.2 U3.6 | length 51.5
  Top Layer w0.203: v1(29.845,68.199) 30.347,68.701 35.152,68.701 U3.6@35.179,68.674 ; v1(64.516,79.756) 64.516,78.232 65.024,77.724 D16.2@65.913,77.724
  Bottom Layer w0.203: v1(29.845,68.199) 30.347,68.701 34.671,68.701 35.312,69.342 35.312,74.933 40.262,79.883 64.389,79.883 v1(64.516,79.756)
NetD18_2: D18.2 U3.7 | length 54.1
  Top Layer w0.203: v1(30.099,67.31) 30.359,67.57 ; 30.359,67.571 31.108,68.32 32.423,68.32 32.569,68.174 U3.7@35.179,68.174 ; v1(67.31,79.121) 68.072,79.121 68.58,78.613 D18.2@68.58,77.725
  Bottom Layer w0.203: v1(30.099,67.31) 31.108,68.32 32.423,68.32 32.671,68.072 35.052,68.072 35.693,68.713 35.693,74.775 40.419,79.502 63.88,79.502 64.255,79.127 67.304,79.127 v1(67.31,79.121)
NetD19_3: D19.3 K2.1 Q19.3 | length 8.6
  Top Layer w0.305: Q19.3@55.88,27.432 D19.3@55.88,23.08 57.497,23.08 58.547,24.13 K2.1@59.69,24.13
NetD21_2: D21.2 U3.8 | length 54.8
  Top Layer w0.203: v1(30.988,67.31) 31.115,67.31 31.375,67.57 ; 31.375,67.571 31.743,67.939 32.265,67.939 32.53,67.674 U3.8@35.179,67.674 ; D21.2@71.12,77.978 v1(71.12,78.867)
  Bottom Layer w0.203: v1(30.988,67.31) 31.114,67.31 31.743,67.939 32.265,67.939 32.513,67.691 35.56,67.691 36.074,68.205 36.074,74.617 39.302,77.845 60.831,77.845 61.091,78.105 65.151,78.105 65.659,77.597 69.85,77.597 v1(71.12,78.867)
NetD23_2: D23.2 U3.9 | length 57.3
  Top Layer w0.203: v1(32.004,67.31) 32.139,67.175 U3.9@35.179,67.175 ; D23.2@73.66,77.725 v1(75.311,77.724) v1(75.311,77.724)
  Bottom Layer w0.203: v1(32.004,67.31) 35.921,67.31 36.455,67.843 36.455,74.46 39.459,77.464 60.989,77.464 61.243,77.718 64.999,77.718 66.009,76.708 74.422,76.708 75.311,77.597 v1(75.311,77.724)
NetGPS1_9: GPS1.9 L8.2 | length 2.2
  Top Layer w0.381: L8.2@145.671,9.527 GPS1.9@145.671,11.749
NetGPS1_20: GPS1.20 P3.13 U3.10 | length 222.5
  Top Layer w0.203: P3.13@20.955,63.5 22.225,64.77 25.146,64.77 27.051,66.675 U3.10@35.179,66.675 ; v1(129.921,78.867) 129.921,73.66 131.191,72.39 140.843,72.39 141.986,71.247 141.986,29.433 140.335,27.782 140.335,25.623 139.371,24.659 GPS1.20@139.371,23.749
  Bottom Layer w0.203: P3.13@20.955,63.5 22.225,64.77 22.225,66.675 22.86,67.31 26.893,67.31 29.179,69.596 32.735,69.596 33.767,70.627 33.767,76.342 38.196,80.772 59.659,80.772 62.611,83.724 62.611,91.852 63.469,92.71 87.153,92.71 89.281,90.582 89.281,83.693 92.075,80.899 127.889,80.899 v1(129.921,78.867)
NetGPS1_21: GPS1.21 P3.12 U3.5 | length 214.8
  Top Layer w0.203: P3.12@23.495,66.04 24.511,66.04 27.645,69.174 U3.5@35.179,69.174 ; v1(129.286,78.105) 129.286,71.628 131.064,69.85 140.843,69.85 141.605,69.088 141.605,29.591 139.954,27.94 139.954,25.781 139.319,25.146 138.43,25.146 138.271,24.987 GPS1.21@138.271,23.749
  Bottom Layer w0.203: P3.12@23.495,66.04 26.162,66.04 29.337,69.215 32.893,69.215 34.163,70.485 34.163,76.2 38.354,80.391 59.817,80.391 62.992,83.566 62.992,91.694 63.627,92.329 86.995,92.329 88.9,90.424 88.9,83.439 91.821,80.518 126.873,80.518 v1(129.286,78.105)
NetGPS1_22: GPS1.22 R123.1 | length 4.5
  Top Layer w0.254: GPS1.22@137.171,23.749 137.171,25.389 137.436,25.654 138.938,25.654 139.192,25.908 R123.1@139.192,26.543
NetJ5_2: J5.2 R49.2 R50.1 U4.6 | length 12.1
  Top Layer w0.254: R49.2@94.869,12.7 96.901,12.7 96.901,7.326 J5.2@95.925,6.35 ; R50.1@96.901,12.827 96.901,13.716 97.155,13.97 97.663,13.97 97.79,14.097 U4.6@97.79,15.507
NetJ5_3: J5.3 R50.2 R54.1 U4.7 | length 12.3
  Top Layer w0.254: U4.7@99.06,15.507 99.06,14.097 99.187,13.97 99.695,13.97 99.949,13.716 R50.2@99.949,12.7 ; J5.3@100.925,6.35 99.949,7.326 R50.2@99.949,12.7 ; R54.1@101.981,12.7 R50.2@99.949,12.7
NetJ7_2: J7.2 R62.2 R65.1 U5.6 | length 12.3
  Top Layer w0.254: R62.2@117.729,12.7 R65.1@119.761,12.7 ; J7.2@118.785,6.35 119.761,7.326 R65.1@119.761,12.7 ; U5.6@120.65,15.507 120.65,14.224 120.523,14.097 120.015,14.097 119.761,13.843 R65.1@119.761,12.7
NetJ7_3: J7.3 R65.2 R68.1 U5.7 | length 12.2
  Top Layer w0.254: U5.7@121.92,15.507 121.92,14.224 122.174,13.97 122.555,13.97 122.809,13.716 R65.2@122.809,12.7 ; J7.3@123.785,6.35 122.809,7.326 R65.2@122.809,12.7 ; R68.1@124.841,12.7 R65.2@122.809,12.7
NetJ8_2: J8.2 U15.15 | length 11.4
  Top Layer w0.203: J8.2@143.637,51.435 147.828,51.435 148.59,52.197 148.59,55.754 149.713,56.877 U15.15@149.713,57.875
NetJ8_3: J8.3 U15.14 | length 15
  Top Layer w0.203: J8.3@143.637,48.895 142.367,50.165 142.367,52.197 142.875,52.705 147.447,52.705 148.209,53.467 148.209,56.007 149.213,57.011 U15.14@149.213,57.875
NetJ11_1: J11.1 R129.2 | length 12.3
  Top Layer w0.762: R129.2@10.922,99.695 R129.2@11.025,99.695 15.113,99.695 16.51,98.298 J11.1@16.51,92.202
NetLCD1_3: LCD1.3 R87.2 | length 30.9
  Top Layer w0.203: R87.2@25.146,91.44 23.876,92.71 23.876,95.377 24.638,96.139 26.162,96.139 29.972,99.949 45.593,99.949 46.87,98.672 LCD1.3@46.87,97.695
NetLCD1_4: LCD1.4 R75.2 U3.119 | length 31
  Top Layer w0.203: LCD1.4@45.87,97.695 45.87,96.751 46.228,96.393 48.418,96.393 49.307,95.504 50.546,95.504 51.435,94.615 51.435,93.599 52.07,93.599 52.324,93.345 52.324,90.17 51.181,89.027 51.181,76.296 50.556,75.671 50.174,75.671 49.628,75.124 U3.119@49.628,73.126
NetLCD1_5: LCD1.5 R76.2 U3.114 | length 32.4
  Top Layer w0.203: LCD1.5@44.87,97.695 44.87,96.354 45.212,96.012 47.752,96.012 49.53,94.234 49.53,93.599 50.165,93.599 50.419,93.345 v1(50.419,89.154) ; U3.114@52.127,73.126 52.127,74.548 53.086,75.507 53.086,82.202 53.588,82.705 53.588,87.92 53.34,88.169 v1(53.34,89.154)
  Bottom Layer w0.203: v1(50.419,89.154) v1(53.34,89.154)
NetLCD1_6: LCD1.6 R77.2 U3.113 | length 34.1
  Top Layer w0.203: LCD1.6@43.87,97.695 43.87,96.211 44.577,95.504 46.609,95.504 47.625,94.488 47.625,93.599 48.26,93.599 48.514,93.345 v1(48.514,89.789) ; U3.113@52.627,73.126 52.627,74.509 53.467,75.349 53.467,82.045 53.969,82.547 53.969,89.783 v1(53.975,89.789)
  Bottom Layer w0.203: v1(48.514,89.789) v1(53.975,89.789)
NetLCD1_7: LCD1.7 R78.2 U3.115 | length 33.5
  Top Layer w0.203: LCD1.7@42.87,97.695 42.87,96.322 44.069,95.123 45.212,95.123 45.72,94.615 45.72,93.599 46.228,93.599 46.609,93.218 v1(46.609,89.154) ; U3.115@51.628,73.126 51.628,74.587 52.705,75.665 52.705,82.36 53.207,82.863 53.207,87.763 v1(52.451,88.519)
  Bottom Layer w0.203: v1(46.609,89.154) 47.244,88.519 v1(52.451,88.519)
NetLCD1_8: LCD1.8 R79.2 U3.116 | length 33.5
  Top Layer w0.203: LCD1.8@41.87,97.695 41.87,96.179 43.815,94.234 43.815,93.599 44.45,93.599 44.704,93.345 v1(44.704,89.154) ; U3.116@51.128,73.126 51.128,74.626 52.324,75.823 52.324,82.518 52.826,83.02 52.826,86.748 v1@51.817,87.757
  Bottom Layer w0.203: v1(44.704,89.154) 46.101,87.757 v1(51.816,87.757)
NetLCD1_9: LCD1.9 R80.2 U3.117 | length 34.4
  Top Layer w0.203: LCD1.9@40.87,97.695 40.87,95.909 41.91,94.869 41.91,93.599 42.545,93.599 42.799,93.345 v1(42.799,89.154) ; U3.117@50.628,73.126 50.628,74.665 51.943,75.98 51.943,82.676 52.445,83.178 52.445,86.239 v1(51.816,86.868)
  Bottom Layer w0.203: v1(42.799,89.154) 45.085,86.868 v1(51.816,86.868)
NetLCD1_10: LCD1.10 R81.2 U3.118 | length 35.1
  Top Layer w0.203: LCD1.10@39.87,97.695 39.87,95.766 40.005,95.631 R81.2@40.005,93.56 40.005,93.472 40.767,93.472 40.894,93.345 40.894,89.281 v1(41.021,89.154) ; U3.118@50.128,73.126 50.128,74.704 51.562,76.138 51.562,83.185 51.816,83.439 v1(51.816,85.852)
  Bottom Layer w0.203: v1(41.021,89.154) 44.323,85.852 v1(51.816,85.852)
NetLCD1_11: LCD1.11 R82.2 U3.132 | length 27.2
  Top Layer w0.203: R82.2@38.1,93.599 38.1,94.488 38.87,95.258 LCD1.11@38.87,97.695 ; R82.2@38.227,93.599 38.735,93.599 38.989,93.345 38.989,86.356 43.13,82.216 U3.132@43.13,73.126
NetLCD1_12: LCD1.12 R83.2 U3.133 | length 28.7
  Top Layer w0.203: LCD1.12@37.87,97.695 37.87,95.655 37.084,94.869 36.449,94.869 36.195,94.615 36.195,93.599 36.83,93.599 37.084,93.345 37.084,87.722 42.63,82.177 U3.133@42.63,73.126
NetLCD1_13: LCD1.13 R84.2 U3.134 | length 30.1
  Top Layer w0.203: R84.2@34.163,93.599 R84.2@34.29,93.599 ; LCD1.13@36.87,97.695 36.87,95.798 36.449,95.377 35.433,95.377 34.29,94.234 R84.2@34.29,93.599 ; U3.134@42.13,73.126 42.13,82.138 35.306,88.962 35.306,93.345 35.052,93.599 R84.2@34.29,93.599
NetLCD1_14: LCD1.14 R85.2 U3.135 | length 31.1
  Top Layer w0.203: R85.2@32.385,93.599 32.385,94.488 32.766,94.869 34.036,94.869 34.925,95.758 35.306,95.758 35.87,96.322 LCD1.14@35.87,97.695 ; R85.2@32.512,93.599 33.02,93.599 33.274,93.345 33.274,90.455 41.63,82.099 U3.135@41.63,73.126
NetLCD1_15: LCD1.15 R86.2 U3.120 | length 46.7
  Top Layer w0.203: v1(31.369,89.154) 31.369,93.472 31.242,93.599 30.48,93.599 30.48,94.869 30.988,95.377 33.751,95.377 34.513,96.139 34.544,96.139 34.87,96.465 LCD1.15@34.87,97.695 ; U3.120@49.128,73.126 49.128,75.163 50.017,76.052 50.398,76.052 50.8,76.454 50.8,82.042 50.419,82.423 v1(50.419,85.217)
  Bottom Layer w0.203: v1(31.369,89.154) 35.306,85.217 v1(50.419,85.217)
NetLCD1_16: LCD1.16 R88.1 U3.138 | length 37.1
  Top Layer w0.203: LCD1.16@33.87,97.695 33.87,96.354 33.401,95.885 29.845,95.885 28.702,94.742 28.702,93.599 29.337,93.599 29.591,93.345 29.591,89.281 31.369,87.503 35.687,87.503 40.894,82.296 40.894,79.121 40.13,78.357 U3.138@40.13,73.126
NetLCD1_17: LCD1.17 R87.3 | length 9.8
  Top Layer w0.203: R87.3@25.146,93.98 27.051,93.98 29.464,96.393 32.512,96.393 32.87,96.751 LCD1.17@32.87,97.695
NetLCD-SPR1_1: LCD-SPR1.1 U3.139 | length 41.6
  Top Layer w0.203: v1(38.354,83.693) 38.354,81.915 39.631,80.638 U3.139@39.631,73.126 ; v1(54.61,84.582) LCD-SPR1.1@54.61,98.425
  Bottom Layer w0.203: v1(38.354,83.693) 52.705,83.693 53.594,84.582 v1(54.61,84.582)
NetLCD-SPR2_1: LCD-SPR2.1 U3.140 | length 44.3
  Top Layer w0.203: v1(37.592,84.455) 37.592,82.138 39.237,80.493 39.237,74.923 39.131,74.817 U3.140@39.131,73.126 ; v1(56.388,85.217) 56.515,85.344 LCD-SPR2.1@56.515,98.298
  Bottom Layer w0.203: v1(37.592,84.455) 52.705,84.455 53.467,85.217 v1(56.388,85.217)
NetLED1_2: LED1.2 R1.2 | length 1.9
  Top Layer w0.203: LED1.2@33.87,10.795 R1.2@35.814,10.795
NetLED2_2: LED2.2 R2.2 | length 1.8
  Top Layer w0.203: LED2.2@92.241,23.241 R2.2@92.241,25.058
NetLED3_2: LED3.2 R8.2 | length 2
  Top Layer w0.203: LED3.2@91.86,36.742 LED3.2@91.86,36.83 R8.2@91.86,38.735
NetLED4_1: LED4.1 R119.2 | length 1.9
  Top Layer w0.203: R119.2@23.241,26.67 LED4.1@25.185,26.67
NetLED5_1: LED5.1 R120.2 | length 2.1
  Top Layer w0.203: R120.2@23.114,22.86 LED5.1@25.185,22.86
NetP2_1: P2.1 Q22.3 R105.2 U16.9 | length 32.4
  Top Layer w0.203: U16.9@15.346,21.073 15.346,23.516 16.51,24.68 16.51,27.626 17.967,29.083 26.289,29.083 27.051,29.845 27.051,34.671 27.94,35.56 P2.1@29.811,35.56 ; Q22.3@29.811,39.116 P2.1@29.811,35.56 ; R105.2@32.17,35.56 P2.1@29.845,35.56 P2.1@29.811,35.56
NetP2_2: P2.2 U3.44 U16.32 | length 54.6
  Top Layer w0.203: v1@11.938,34.544 v1(11.938,34.417) 11.938,32.1 13.346,30.692 U16.32@13.346,29.473 ; U3.44@40.63,51.726 40.63,45.379 41.656,44.354 41.656,33.782 v1(40.894,33.02)
  Bottom Layer w0.203: v1(11.938,34.417) 17.907,34.417 18.034,34.544 20.516,34.544 20.529,34.531 25.286,34.531 26.797,33.02 P2.2@29.845,33.02 ; P2.2@29.972,33.02 v1(40.894,33.02)
NetP2_3: P2.3 U3.43 U16.31 | length 56.3
  Top Layer w0.203: v1(12.7,33.782) 12.7,31.877 13.846,30.731 U16.31@13.846,29.473 ; U3.43@40.13,51.726 40.13,45.341 41.275,44.196 41.275,34.798 40.259,33.782 v1(40.259,32.004)
  Bottom Layer w0.203: v1(12.7,33.782) 18.034,33.782 18.415,34.163 20.358,34.163 20.371,34.15 25.032,34.15 25.527,33.655 25.527,31.496 26.543,30.48 P2.3@29.718,30.48 ; P2.3@29.972,30.48 34.417,30.48 35.941,32.004 v1(40.259,32.004)
NetP2_4: P2.4 U3.46 U16.34 | length 57.2
  Top Layer w0.203: v1(12.319,27.686) U16.34@12.319,29.337 ; U3.46@41.63,51.726 41.63,45.457 42.418,44.669 42.418,28.194 v1(42.672,27.94)
  Bottom Layer w0.203: v1(12.319,27.686) 13.334,27.686 14.09,28.442 14.895,28.442 15.652,27.686 19.303,27.686 19.551,27.438 28.2,27.438 28.702,27.94 P2.4@29.845,27.94 v1(42.672,27.94)
NetP2_5: P2.5 U3.45 U16.33 | length 59.2
  Top Layer w0.203: v1(12.827,26.924) 12.948,27.045 12.948,27.947 12.847,28.048 U16.33@12.847,29.473 ; U3.45@41.13,51.726 41.13,45.418 42.037,44.512 v1(42.037,25.4)
  Bottom Layer w0.203: v1(12.827,26.924) 18.542,26.924 20.066,25.4 P2.5@29.845,25.4 v1(42.037,25.4)
NetP2_6: P2.6 R108.2 U16.10 | length 19.7
  Top Layer w0.203: U16.10@15.846,21.073 15.846,22.704 v1(16.256,23.114) ; P2.6@29.845,22.86 R108.2@32.805,22.86
  Bottom Layer w0.203: v1(16.256,23.114) 17.526,21.844 28.829,21.844 P2.6@29.845,22.86
NetP3_9: P3.9 U3.1 | length 15.8
  Top Layer w0.203: P3.9@20.955,68.58 22.225,69.85 26.289,69.85 28.194,71.755 32.893,71.755 33.474,71.174 U3.1@35.179,71.174
NetP3_10: P3.10 U3.3 | length 12.3
  Top Layer w0.203: P3.10@23.495,68.58 25.781,68.58 27.375,70.174 U3.3@35.179,70.174
NetP3_11: P3.11 U3.4 | length 15.7
  Top Layer w0.203: P3.11@20.955,66.04 22.225,67.31 25.146,67.31 27.51,69.674 U3.4@35.179,69.674
NetP3_14: P3.14 U3.20 | length 12.4
  Top Layer w0.203: P3.14@23.495,63.5 26.035,63.5 27.859,61.676 U3.20@35.179,61.676
NetP3_15: P3.15 U3.25 | length 16.7
  Top Layer w0.203: P3.15@20.955,60.96 22.225,62.23 25.526,62.23 29.463,58.293 32.766,58.293 33.65,59.177 U3.25@35.179,59.177
NetP3_16: P3.16 U3.26 | length 13.1
  Top Layer w0.203: P3.16@23.622,60.96 26.257,60.96 29.305,57.912 32.924,57.912 33.689,58.677 U3.26@35.179,58.677
NetP3_17: P3.17 U3.27 | length 15.9
  Top Layer w0.203: P3.17@20.955,58.42 22.225,59.69 26.988,59.69 29.147,57.531 33.082,57.531 33.727,58.177 U3.27@35.179,58.177
NetP3_18: P3.18 U3.28 | length 12.4
  Top Layer w0.203: P3.18@23.495,58.42 27.719,58.42 28.989,57.15 33.239,57.15 33.766,57.677 U3.28@35.179,57.677
NetP3_19: P3.19 U3.30 | length 15.1
  Top Layer w0.203: P3.19@21.082,56.007 22.225,57.15 25.781,57.15 26.162,57.531 28.07,57.531 28.923,56.677 U3.30@35.179,56.677
NetP3_20: P3.20 U3.31 | length 12.9
  Top Layer w0.203: P3.20@23.241,56.007 23.32,55.928 P3.20@23.495,55.928 ; P3.20@23.495,55.88 25.273,55.88 26.543,57.15 27.912,57.15 28.884,56.177 U3.31@35.179,56.177
NetP3_21: P3.21 U3.32 | length 15.2
  Top Layer w0.203: P3.21@20.955,53.34 22.098,54.483 24.511,54.483 24.879,54.851 28.308,54.851 29.135,55.678 U3.32@35.179,55.678
NetP3_22: P3.22 U3.33 | length 12.4
  Top Layer w0.203: P3.22@23.495,53.34 24.905,53.34 26.035,54.47 28.466,54.47 29.173,55.178 U3.33@35.179,55.178
NetP3_23: P3.23 U3.37 | length 18.7
  Top Layer w0.203: P3.23@20.955,50.8 22.225,52.07 24.384,52.07 24.625,52.311 30.493,52.311 32.385,50.419 36.83,50.419 37.131,50.72 U3.37@37.131,51.726
NetP3_24: P3.24 U3.38 | length 16.8
  Top Layer w0.203: P3.24@23.495,50.8 24.397,50.8 25.527,51.93 30.335,51.93 32.227,50.038 37.084,50.038 37.631,50.585 U3.38@37.631,51.726
NetP3_25: P3.25 U3.39 | length 19.4
  Top Layer w0.203: P3.25@20.955,48.26 22.225,49.53 25.019,49.53 25.26,49.771 31.955,49.771 32.069,49.657 37.242,49.657 38.131,50.546 U3.39@38.131,51.726
NetP3_26: P3.26 U3.40 | length 17.4
  Top Layer w0.203: P3.26@23.495,48.26 24.778,48.26 25.908,49.39 31.496,49.39 31.61,49.276 37.4,49.276 38.631,50.507 U3.40@38.631,51.726
NetP3_27: P3.27 U3.47 | length 28
  Top Layer w0.203: P3.27@20.955,45.72 22.225,46.99 25.273,46.99 25.514,47.231 31.737,47.231 v1(33.147,48.641) ; v1(38.1,54.864) 40.767,54.864 42.13,53.501 U3.47@42.13,51.726
  Bottom Layer w0.203: v1(33.147,48.641) 38.1,53.594 v1(38.1,54.864)
NetP3_28: P3.28 U3.56 | length 33.4
  Top Layer w0.203: v1(46.609,43.053) 47.244,43.688 47.244,49.653 46.629,50.268 U3.56@46.629,51.726
  Bottom Layer w0.203: P3.28@23.495,45.72 25.146,45.72 26.416,44.45 29.972,44.45 31.369,43.053 v1(46.609,43.053)
NetP3_29: P3.29 U3.74 | length 51.2
  Top Layer w0.203: U3.74@56.579,54.178 57.681,54.178 57.913,53.946 57.913,51.712 ; 57.912,51.711 57.912,46.009 58.42,45.501 v1(58.42,44.45)
  Bottom Layer w0.203: P3.29@20.955,43.18 22.225,44.45 24.268,44.45 26.567,42.151 28.297,42.151 28.31,42.164 30.734,42.164 31.242,42.672 46.1,42.672 46.348,42.424 48.139,42.424 50.165,44.45 v1(58.42,44.45)
NetP3_30: P3.30 U3.76 | length 51.1
  Top Layer w0.203: U3.76@56.579,55.178 57.759,55.178 58.675,54.262 58.675,51.396 58.674,46.324 59.436,45.562 59.436,43.815 v1(59.563,43.688)
  Bottom Layer w0.203: P3.30@23.495,43.18 24.999,43.18 26.409,41.77 30.879,41.77 31.4,42.291 45.942,42.291 46.19,42.043 48.296,42.043 49.942,43.688 v1(59.563,43.688)
NetP3_31: P3.31 U3.77 | length 56.5
  Top Layer w0.203: U3.77@56.579,55.678 56.647,55.609 57.866,55.609 59.056,54.42 59.056,51.238 59.055,46.482 60.325,45.212 v1(60.325,43.053)
  Bottom Layer w0.203: P3.31@20.955,40.64 22.466,42.151 23.921,42.151 23.934,42.164 25.477,42.164 26.251,41.389 28.702,41.389 29.07,41.021 33.4,41.021 33.521,40.9 34.043,40.9 35.053,41.91 45.784,41.91 46.033,41.662 48.454,41.662 49.846,43.053 v1(60.325,43.053)
NetP3_32: P3.32 R92.2 U3.78 | length 54.7
  Top Layer w0.203: P3.32@23.495,40.64 25.146,40.64 25.4,40.894 27.686,40.894 v1(27.94,40.64) ; U3.78@56.579,56.177 57.837,56.177 59.437,54.577 59.437,51.081 ; 59.436,51.08 59.436,46.64 60.954,45.121 60.954,42.792 60.586,42.424 ; v1(60.325,42.037) 60.585,42.297 60.585,42.424
  Bottom Layer w0.203: v1(27.94,40.64) 33.242,40.64 33.363,40.519 34.201,40.519 34.957,41.275 48.606,41.275 49.368,42.037 v1(60.325,42.037)
NetP3_33: P3.33 U3.79 | length 60
  Top Layer w0.203: U3.79@56.579,56.677 58.127,56.677 59.818,54.987 59.818,50.923 ; 59.817,50.922 59.817,46.798 61.335,45.279 61.335,42.634 61.087,42.386 v1(61.087,41.402)
  Bottom Layer w0.203: P3.33@20.955,38.1 22.466,39.611 23.921,39.611 24.32,40.011 34.231,40.011 35.115,40.894 48.764,40.894 49.526,41.656 59.816,41.656 60.064,41.408 61.081,41.408 v1(61.087,41.402)
NetP3_34: P3.34 U3.80 | length 61.1
  Top Layer w0.203: U3.80@56.579,57.177 58.166,57.177 60.199,55.145 60.199,50.765 60.198,46.955 61.716,45.437 v1@61.716,38.233 ; v1(61.722,38.227) v1@61.722,38.233
  Bottom Layer w0.203: P3.34@23.495,38.1 27.305,38.1 28.454,39.249 44.323,39.249 45.345,38.227 v1(61.722,38.227)
NetP4_9: P4.9 U3.85 | length 113.8
  Top Layer w0.203: U3.85@56.579,59.676 58.039,59.676 59.309,58.406 59.309,56.642 60.58,55.371 60.58,50.607 60.579,48.132 v1(63.5,45.212) ; v1(126.365,47.498) 126.492,47.625 126.492,49.403 127.381,50.292 127.381,53.94 128.432,54.991 134.685,54.991 135.763,56.069 135.763,59.721 136.271,60.229 136.271,67.056 P4.9@137.795,68.58
  Bottom Layer w0.203: v1(63.5,45.212) 64.262,45.212 64.764,45.714 77.922,45.714 78.424,45.212 81.118,45.212 84.293,48.387 85.725,48.387 87.122,49.784 124.079,49.784 v1(126.365,47.498)
NetP4_10: P4.10 U3.86 | length 115.4
  Top Layer w0.203: U3.86@56.579,60.176 58.078,60.176 59.69,58.564 59.69,56.8 60.961,55.529 60.961,50.449 ; 60.96,50.449 60.96,48.64 v1(63.5,46.101) ; v1(127.254,47.752) 127.26,47.758 127.26,49.314 127.762,49.816 127.762,53.783 128.589,54.61 134.843,54.61 136.144,55.911 136.144,59.563 136.652,60.071 136.652,66.352 137.369,67.069 138.824,67.069 P4.10@140.335,68.58
  Bottom Layer w0.203: v1(63.5,46.101) 67.426,46.101 67.431,46.095 78.08,46.095 78.582,45.593 80.961,45.593 84.136,48.768 85.344,48.768 86.741,50.165 124.237,50.165 126.015,48.387 126.619,48.387 v1(127.254,47.752)
NetP4_11: P4.11 U3.87 | length 112.1
  Top Layer w0.203: U3.87@56.579,60.676 58.166,60.676 58.166,60.627 60.071,58.722 60.071,56.958 61.342,55.687 61.342,49.147 v1(63.5,46.99) ; v1(127.889,48.514) 127.895,48.52 127.895,49.41 128.143,49.658 128.143,53.625 128.747,54.229 135.001,54.229 136.525,55.753 136.525,59.182 137.033,59.69 138.43,59.69 138.925,60.185 138.925,64.91 P4.11@137.795,66.04
  Bottom Layer w0.203: v1(63.5,46.99) 64.389,46.99 64.897,46.482 78.232,46.482 78.74,45.974 80.803,45.974 83.978,49.149 85.186,49.149 86.583,50.546 124.395,50.546 126.173,48.768 127.635,48.768 v1(127.889,48.514)
NetP4_12: P4.12 U3.88 | length 112.2
  Top Layer w0.203: U3.88@56.579,61.176 58.205,61.176 60.452,58.929 60.452,57.115 61.723,55.845 61.723,49.656 v1(63.5,47.879) ; v1(128.524,49.149) 128.524,53.467 128.905,53.848 136.848,53.848 137.369,54.369 138.062,54.369 139.306,55.613 139.306,65.011 P4.12@140.335,66.04
  Bottom Layer w0.203: v1(63.5,47.879) 63.881,47.879 64.389,47.371 77.882,47.371 78.898,46.355 80.645,46.355 83.82,49.53 85.028,49.53 86.425,50.927 124.552,50.927 126.33,49.149 v1(128.524,49.149)
NetP4_13: P4.13 U3.93 | length 89.4
  Top Layer w0.203: v1(52.959,63.5) 53.213,63.5 53.588,63.875 54.617,63.875 54.817,63.675 U3.93@56.579,63.675
  Bottom Layer w0.203: v1(52.959,63.5) 53.848,62.611 134.62,62.611 135.509,63.5 P4.13@137.795,63.5
NetP4_14: P4.14 U3.94 | length 86.3
  Top Layer w0.203: U3.94@56.579,64.175 58.253,64.175 v1(58.293,64.135)
  Bottom Layer w0.203: v1(58.293,64.135) 59.436,62.992 75.564,62.992 76.574,64.002 77.096,64.002 78.106,62.992 134.366,62.992 136.144,64.77 139.065,64.77 P4.14@140.335,63.5
NetP4_15: P4.15 U3.95 | length 92.7
  Top Layer w0.203: v1(54.356,64.643) 54.388,64.675 U3.95@56.579,64.675
  Bottom Layer w0.203: v1(54.356,64.643) 53.212,64.643 52.33,63.761 52.33,62.858 54.095,61.093 54.617,61.093 55.754,62.23 134.747,62.23 136.017,60.96 P4.15@137.795,60.96
NetP4_16: P4.16 U3.96 | length 101.1
  Top Layer w0.203: U3.96@56.579,65.175 58.269,65.175 v1(58.293,65.151)
  Bottom Layer w0.203: v1(58.293,65.151) 58.172,65.272 54.095,65.272 53.847,65.024 53.054,65.024 51.949,63.919 51.949,62.7 53.937,60.712 54.775,60.712 55.912,61.849 134.493,61.849 136.652,59.69 138.938,59.69 P4.16@140.335,61.087
NetP4_17: P4.17 U3.97 | length 96.2
  Top Layer w0.203: v1(53.213,65.786) 53.324,65.675 U3.97@56.579,65.675
  Bottom Layer w0.203: v1(53.213,65.786) 53.213,65.722 51.568,64.076 51.568,62.543 53.78,60.331 54.932,60.331 56.07,61.468 133.477,61.468 136.525,58.42 P4.17@137.795,58.42
NetP4_18: P4.18 U3.98 | length 106.7
  Top Layer w0.203: U3.98@56.579,66.175 59.047,66.175 v1(59.055,66.167)
  Bottom Layer w0.203: v1(59.055,66.167) 58.934,66.046 54.095,66.046 53.725,66.415 52.952,66.415 51.187,64.65 51.187,62.385 53.622,59.95 55.09,59.95 56.228,61.087 133.319,61.087 136.144,58.262 136.144,57.531 136.525,57.15 139.192,57.15 P4.18@140.335,58.293
NetP4_19: P4.19 U3.99 | length 100.7
  Top Layer w0.203: v1@54.356,66.675 U3.99@56.579,66.675
  Bottom Layer w0.203: v1(54.356,66.675) 54.235,66.796 52.794,66.796 50.806,64.808 50.806,62.227 53.464,59.569 55.248,59.569 56.385,60.706 133.161,60.706 135.763,58.104 135.763,56.515 136.398,55.88 P4.19@137.795,55.88
NetP4_20: P4.20 U3.100 | length 109.1
  Top Layer w0.203: U3.100@56.579,67.175 58.285,67.175 v1(58.293,67.183)
  Bottom Layer w0.203: v1(58.293,67.183) 58.172,67.304 52.764,67.304 50.425,64.965 50.425,62.069 53.306,59.188 55.406,59.188 56.543,60.325 132.969,60.325 135.382,57.912 135.382,56.261 137.033,54.61 139.192,54.61 P4.20@140.462,55.88
NetP4_21: P4.21 U3.101 | length 105.1
  Top Layer w0.203: v1(51.816,67.691) 53.34,67.691 53.357,67.674 U3.101@56.579,67.674
  Bottom Layer w0.203: v1(51.816,67.691) 51.816,66.896 50.044,65.123 50.044,61.911 53.148,58.807 55.564,58.807 55.812,59.055 59.425,59.055 59.43,59.061 65.666,59.061 66.549,59.944 132.811,59.944 135.001,57.754 135.001,54.991 136.652,53.34 P4.21@137.795,53.34
NetP4_22: P4.22 U3.104 | length 117.3
  Top Layer w0.203: U3.104@56.579,69.174 56.647,69.106 57.749,69.106 57.767,69.088 v1(58.42,69.088)
  Bottom Layer w0.203: v1(58.42,69.088) 58.172,69.336 54.095,69.336 53.847,69.088 51.245,69.088 48.901,66.743 48.901,60.064 50.539,58.426 59.334,58.426 59.588,58.68 65.824,58.68 66.707,59.563 132.588,59.563 134.62,57.531 134.62,54.483 137.033,52.07 139.065,52.07 P4.22@140.335,53.34
NetP4_23: P4.23 U3.105 | length 118.7
  Top Layer w0.203: U3.105@56.579,69.674 56.622,69.717 59.315,69.717 v1(59.563,69.469)
  Bottom Layer w0.203: v1(59.563,69.469) 59.309,69.723 51.341,69.723 48.52,66.901 48.52,59.906 50.381,58.045 59.492,58.045 59.746,58.299 65.981,58.299 66.865,59.182 132.334,59.182 134.239,57.277 134.239,53.975 136.271,51.943 136.271,51.308 136.779,50.8 P4.23@137.795,50.8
